VERSION 5.4 ;
NAMESCASESENSITIVE ON ;
BUSBITCHARS "[]" ;
DIVIDERCHAR "/" ;
UNITS
  DATABASE MICRONS 2000 ;
END UNITS
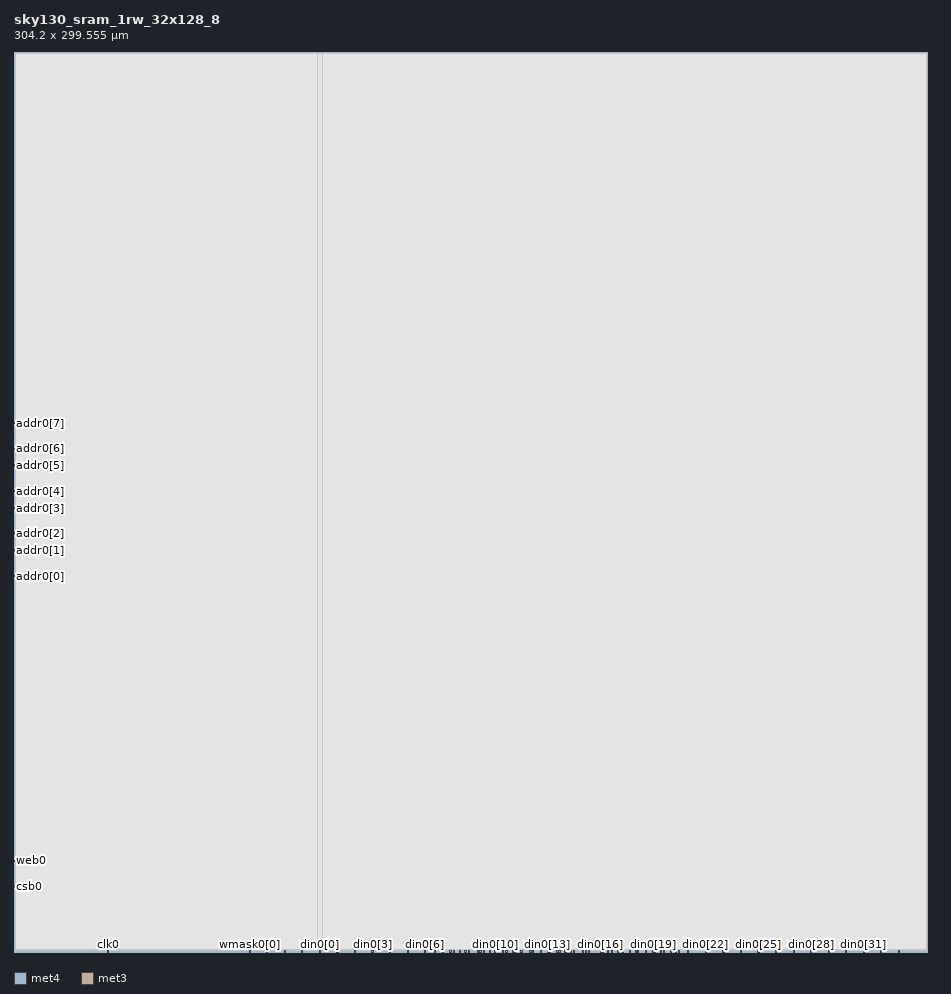
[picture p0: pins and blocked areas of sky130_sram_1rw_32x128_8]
MACRO sky130_sram_1rw_32x128_8
   CLASS BLOCK ;
   SIZE 304.2 BY 299.555 ;
   SYMMETRY X Y R90 ;
   PIN din0[0]
      DIRECTION INPUT ;
      PORT
         LAYER met4 ;
         RECT  101.62 0.0 102.0 0.38 ;
      END
   END din0[0]
   PIN din0[1]
      DIRECTION INPUT ;
      PORT
         LAYER met4 ;
         RECT  107.46 0.0 107.84 0.38 ;
      END
   END din0[1]
   PIN din0[2]
      DIRECTION INPUT ;
      PORT
         LAYER met4 ;
         RECT  113.3 0.0 113.68 0.38 ;
      END
   END din0[2]
   PIN din0[3]
      DIRECTION INPUT ;
      PORT
         LAYER met4 ;
         RECT  119.14 0.0 119.52 0.38 ;
      END
   END din0[3]
   PIN din0[4]
      DIRECTION INPUT ;
      PORT
         LAYER met4 ;
         RECT  124.98 0.0 125.36 0.38 ;
      END
   END din0[4]
   PIN din0[5]
      DIRECTION INPUT ;
      PORT
         LAYER met4 ;
         RECT  130.82 0.0 131.2 0.38 ;
      END
   END din0[5]
   PIN din0[6]
      DIRECTION INPUT ;
      PORT
         LAYER met4 ;
         RECT  136.66 0.0 137.04 0.38 ;
      END
   END din0[6]
   PIN din0[7]
      DIRECTION INPUT ;
      PORT
         LAYER met4 ;
         RECT  142.5 0.0 142.88 0.38 ;
      END
   END din0[7]
   PIN din0[8]
      DIRECTION INPUT ;
      PORT
         LAYER met4 ;
         RECT  148.34 0.0 148.72 0.38 ;
      END
   END din0[8]
   PIN din0[9]
      DIRECTION INPUT ;
      PORT
         LAYER met4 ;
         RECT  154.18 0.0 154.56 0.38 ;
      END
   END din0[9]
   PIN din0[10]
      DIRECTION INPUT ;
      PORT
         LAYER met4 ;
         RECT  160.02 0.0 160.4 0.38 ;
      END
   END din0[10]
   PIN din0[11]
      DIRECTION INPUT ;
      PORT
         LAYER met4 ;
         RECT  165.86 0.0 166.24 0.38 ;
      END
   END din0[11]
   PIN din0[12]
      DIRECTION INPUT ;
      PORT
         LAYER met4 ;
         RECT  171.7 0.0 172.08 0.38 ;
      END
   END din0[12]
   PIN din0[13]
      DIRECTION INPUT ;
      PORT
         LAYER met4 ;
         RECT  177.54 0.0 177.92 0.38 ;
      END
   END din0[13]
   PIN din0[14]
      DIRECTION INPUT ;
      PORT
         LAYER met4 ;
         RECT  183.38 0.0 183.76 0.38 ;
      END
   END din0[14]
   PIN din0[15]
      DIRECTION INPUT ;
      PORT
         LAYER met4 ;
         RECT  189.22 0.0 189.6 0.38 ;
      END
   END din0[15]
   PIN din0[16]
      DIRECTION INPUT ;
      PORT
         LAYER met4 ;
         RECT  195.06 0.0 195.44 0.38 ;
      END
   END din0[16]
   PIN din0[17]
      DIRECTION INPUT ;
      PORT
         LAYER met4 ;
         RECT  200.9 0.0 201.28 0.38 ;
      END
   END din0[17]
   PIN din0[18]
      DIRECTION INPUT ;
      PORT
         LAYER met4 ;
         RECT  206.74 0.0 207.12 0.38 ;
      END
   END din0[18]
   PIN din0[19]
      DIRECTION INPUT ;
      PORT
         LAYER met4 ;
         RECT  212.58 0.0 212.96 0.38 ;
      END
   END din0[19]
   PIN din0[20]
      DIRECTION INPUT ;
      PORT
         LAYER met4 ;
         RECT  218.42 0.0 218.8 0.38 ;
      END
   END din0[20]
   PIN din0[21]
      DIRECTION INPUT ;
      PORT
         LAYER met4 ;
         RECT  224.26 0.0 224.64 0.38 ;
      END
   END din0[21]
   PIN din0[22]
      DIRECTION INPUT ;
      PORT
         LAYER met4 ;
         RECT  230.1 0.0 230.48 0.38 ;
      END
   END din0[22]
   PIN din0[23]
      DIRECTION INPUT ;
      PORT
         LAYER met4 ;
         RECT  235.94 0.0 236.32 0.38 ;
      END
   END din0[23]
   PIN din0[24]
      DIRECTION INPUT ;
      PORT
         LAYER met4 ;
         RECT  241.78 0.0 242.16 0.38 ;
      END
   END din0[24]
   PIN din0[25]
      DIRECTION INPUT ;
      PORT
         LAYER met4 ;
         RECT  247.62 0.0 248.0 0.38 ;
      END
   END din0[25]
   PIN din0[26]
      DIRECTION INPUT ;
      PORT
         LAYER met4 ;
         RECT  253.46 0.0 253.84 0.38 ;
      END
   END din0[26]
   PIN din0[27]
      DIRECTION INPUT ;
      PORT
         LAYER met4 ;
         RECT  259.3 0.0 259.68 0.38 ;
      END
   END din0[27]
   PIN din0[28]
      DIRECTION INPUT ;
      PORT
         LAYER met4 ;
         RECT  265.14 0.0 265.52 0.38 ;
      END
   END din0[28]
   PIN din0[29]
      DIRECTION INPUT ;
      PORT
         LAYER met4 ;
         RECT  270.98 0.0 271.36 0.38 ;
      END
   END din0[29]
   PIN din0[30]
      DIRECTION INPUT ;
      PORT
         LAYER met4 ;
         RECT  276.82 0.0 277.2 0.38 ;
      END
   END din0[30]
   PIN din0[31]
      DIRECTION INPUT ;
      PORT
         LAYER met4 ;
         RECT  282.66 0.0 283.04 0.38 ;
      END
   END din0[31]
   PIN din0[32]
      DIRECTION INPUT ;
      PORT
         LAYER met4 ;
         RECT  288.5 0.0 288.88 0.38 ;
      END
   END din0[32]
   PIN addr0[0]
      DIRECTION INPUT ;
      PORT
         LAYER met3 ;
         RECT  0.0 124.95 0.38 125.33 ;
      END
   END addr0[0]
   PIN addr0[1]
      DIRECTION INPUT ;
      PORT
         LAYER met3 ;
         RECT  0.0 133.45 0.38 133.83 ;
      END
   END addr0[1]
   PIN addr0[2]
      DIRECTION INPUT ;
      PORT
         LAYER met3 ;
         RECT  0.0 139.09 0.38 139.47 ;
      END
   END addr0[2]
   PIN addr0[3]
      DIRECTION INPUT ;
      PORT
         LAYER met3 ;
         RECT  0.0 147.59 0.38 147.97 ;
      END
   END addr0[3]
   PIN addr0[4]
      DIRECTION INPUT ;
      PORT
         LAYER met3 ;
         RECT  0.0 153.23 0.38 153.61 ;
      END
   END addr0[4]
   PIN addr0[5]
      DIRECTION INPUT ;
      PORT
         LAYER met3 ;
         RECT  0.0 161.73 0.38 162.11 ;
      END
   END addr0[5]
   PIN addr0[6]
      DIRECTION INPUT ;
      PORT
         LAYER met3 ;
         RECT  0.0 167.37 0.38 167.75 ;
      END
   END addr0[6]
   PIN addr0[7]
      DIRECTION INPUT ;
      PORT
         LAYER met3 ;
         RECT  0.0 175.87 0.38 176.25 ;
      END
   END addr0[7]
   PIN csb0
      DIRECTION INPUT ;
      PORT
         LAYER met3 ;
         RECT  0.0 21.61 0.38 21.99 ;
      END
   END csb0
   PIN web0
      DIRECTION INPUT ;
      PORT
         LAYER met3 ;
         RECT  0.0 30.11 0.38 30.49 ;
      END
   END web0
   PIN clk0
      DIRECTION INPUT ;
      PORT
         LAYER met4 ;
         RECT  31.1 0.0 31.48 0.38 ;
      END
   END clk0
   PIN wmask0[0]
      DIRECTION INPUT ;
      PORT
         LAYER met4 ;
         RECT  78.26 0.0 78.64 0.38 ;
      END
   END wmask0[0]
   PIN wmask0[1]
      DIRECTION INPUT ;
      PORT
         LAYER met4 ;
         RECT  84.1 0.0 84.48 0.38 ;
      END
   END wmask0[1]
   PIN wmask0[2]
      DIRECTION INPUT ;
      PORT
         LAYER met4 ;
         RECT  89.94 0.0 90.32 0.38 ;
      END
   END wmask0[2]
   PIN wmask0[3]
      DIRECTION INPUT ;
      PORT
         LAYER met4 ;
         RECT  95.78 0.0 96.16 0.38 ;
      END
   END wmask0[3]
   PIN spare_wen0
      DIRECTION INPUT ;
      PORT
         LAYER met4 ;
         RECT  294.34 0.0 294.72 0.38 ;
      END
   END spare_wen0
   PIN dout0[0]
      DIRECTION OUTPUT ;
      PORT
         LAYER met4 ;
         RECT  139.985 0.0 140.365 0.38 ;
      END
   END dout0[0]
   PIN dout0[1]
      DIRECTION OUTPUT ;
      PORT
         LAYER met4 ;
         RECT  145.1 0.0 145.48 0.38 ;
      END
   END dout0[1]
   PIN dout0[2]
      DIRECTION OUTPUT ;
      PORT
         LAYER met4 ;
         RECT  146.25 0.0 146.63 0.38 ;
      END
   END dout0[2]
   PIN dout0[3]
      DIRECTION OUTPUT ;
      PORT
         LAYER met4 ;
         RECT  150.1 0.0 150.48 0.38 ;
      END
   END dout0[3]
   PIN dout0[4]
      DIRECTION OUTPUT ;
      PORT
         LAYER met4 ;
         RECT  151.25 0.0 151.63 0.38 ;
      END
   END dout0[4]
   PIN dout0[5]
      DIRECTION OUTPUT ;
      PORT
         LAYER met4 ;
         RECT  155.1 0.0 155.48 0.38 ;
      END
   END dout0[5]
   PIN dout0[6]
      DIRECTION OUTPUT ;
      PORT
         LAYER met4 ;
         RECT  156.25 0.0 156.63 0.38 ;
      END
   END dout0[6]
   PIN dout0[7]
      DIRECTION OUTPUT ;
      PORT
         LAYER met4 ;
         RECT  158.215 0.0 158.595 0.38 ;
      END
   END dout0[7]
   PIN dout0[8]
      DIRECTION OUTPUT ;
      PORT
         LAYER met4 ;
         RECT  162.63 0.0 163.01 0.38 ;
      END
   END dout0[8]
   PIN dout0[9]
      DIRECTION OUTPUT ;
      PORT
         LAYER met4 ;
         RECT  163.72 0.0 164.1 0.38 ;
      END
   END dout0[9]
   PIN dout0[10]
      DIRECTION OUTPUT ;
      PORT
         LAYER met4 ;
         RECT  166.55 0.0 166.93 0.38 ;
      END
   END dout0[10]
   PIN dout0[11]
      DIRECTION OUTPUT ;
      PORT
         LAYER met4 ;
         RECT  168.72 0.0 169.1 0.38 ;
      END
   END dout0[11]
   PIN dout0[12]
      DIRECTION OUTPUT ;
      PORT
         LAYER met4 ;
         RECT  172.63 0.0 173.01 0.38 ;
      END
   END dout0[12]
   PIN dout0[13]
      DIRECTION OUTPUT ;
      PORT
         LAYER met4 ;
         RECT  175.1 0.0 175.48 0.38 ;
      END
   END dout0[13]
   PIN dout0[14]
      DIRECTION OUTPUT ;
      PORT
         LAYER met4 ;
         RECT  178.23 0.0 178.61 0.38 ;
      END
   END dout0[14]
   PIN dout0[15]
      DIRECTION OUTPUT ;
      PORT
         LAYER met4 ;
         RECT  181.395 0.0 181.775 0.38 ;
      END
   END dout0[15]
   PIN dout0[16]
      DIRECTION OUTPUT ;
      PORT
         LAYER met4 ;
         RECT  180.705 0.0 181.085 0.38 ;
      END
   END dout0[16]
   PIN dout0[17]
      DIRECTION OUTPUT ;
      PORT
         LAYER met4 ;
         RECT  185.1 0.0 185.48 0.38 ;
      END
   END dout0[17]
   PIN dout0[18]
      DIRECTION OUTPUT ;
      PORT
         LAYER met4 ;
         RECT  186.25 0.0 186.63 0.38 ;
      END
   END dout0[18]
   PIN dout0[19]
      DIRECTION OUTPUT ;
      PORT
         LAYER met4 ;
         RECT  190.1 0.0 190.48 0.38 ;
      END
   END dout0[19]
   PIN dout0[20]
      DIRECTION OUTPUT ;
      PORT
         LAYER met4 ;
         RECT  191.25 0.0 191.63 0.38 ;
      END
   END dout0[20]
   PIN dout0[21]
      DIRECTION OUTPUT ;
      PORT
         LAYER met4 ;
         RECT  195.75 0.0 196.13 0.38 ;
      END
   END dout0[21]
   PIN dout0[22]
      DIRECTION OUTPUT ;
      PORT
         LAYER met4 ;
         RECT  197.63 0.0 198.01 0.38 ;
      END
   END dout0[22]
   PIN dout0[23]
      DIRECTION OUTPUT ;
      PORT
         LAYER met4 ;
         RECT  198.72 0.0 199.1 0.38 ;
      END
   END dout0[23]
   PIN dout0[24]
      DIRECTION OUTPUT ;
      PORT
         LAYER met4 ;
         RECT  202.63 0.0 203.01 0.38 ;
      END
   END dout0[24]
   PIN dout0[25]
      DIRECTION OUTPUT ;
      PORT
         LAYER met4 ;
         RECT  204.935 0.0 205.315 0.38 ;
      END
   END dout0[25]
   PIN dout0[26]
      DIRECTION OUTPUT ;
      PORT
         LAYER met4 ;
         RECT  207.63 0.0 208.01 0.38 ;
      END
   END dout0[26]
   PIN dout0[27]
      DIRECTION OUTPUT ;
      PORT
         LAYER met4 ;
         RECT  210.1 0.0 210.48 0.38 ;
      END
   END dout0[27]
   PIN dout0[28]
      DIRECTION OUTPUT ;
      PORT
         LAYER met4 ;
         RECT  213.27 0.0 213.65 0.38 ;
      END
   END dout0[28]
   PIN dout0[29]
      DIRECTION OUTPUT ;
      PORT
         LAYER met4 ;
         RECT  215.1 0.0 215.48 0.38 ;
      END
   END dout0[29]
   PIN dout0[30]
      DIRECTION OUTPUT ;
      PORT
         LAYER met4 ;
         RECT  216.25 0.0 216.63 0.38 ;
      END
   END dout0[30]
   PIN dout0[31]
      DIRECTION OUTPUT ;
      PORT
         LAYER met4 ;
         RECT  220.1 0.0 220.48 0.38 ;
      END
   END dout0[31]
   PIN dout0[32]
      DIRECTION OUTPUT ;
      PORT
         LAYER met4 ;
         RECT  221.25 0.0 221.63 0.38 ;
      END
   END dout0[32]
   PIN vccd1
      DIRECTION INOUT ;
      USE POWER ; 
      SHAPE ABUTMENT ; 
      PORT
      END
   END vccd1
   PIN vssd1
      DIRECTION INOUT ;
      USE GROUND ; 
      SHAPE ABUTMENT ; 
      PORT
      END
   END vssd1
   OBS
   LAYER  met1 ;
      RECT  0.62 0.62 303.58 298.935 ;
   LAYER  met2 ;
      RECT  0.62 0.62 303.58 298.935 ;
   LAYER  met3 ;
      RECT  0.98 0.62 303.58 124.35 ;
      RECT  0.98 124.35 303.58 125.93 ;
      RECT  0.98 125.93 303.58 298.935 ;
      RECT  0.62 125.93 0.98 132.85 ;
      RECT  0.62 134.43 0.98 138.49 ;
      RECT  0.62 140.07 0.98 146.99 ;
      RECT  0.62 148.57 0.98 152.63 ;
      RECT  0.62 154.21 0.98 161.13 ;
      RECT  0.62 162.71 0.98 166.77 ;
      RECT  0.62 168.35 0.98 175.27 ;
      RECT  0.62 176.85 0.98 298.935 ;
      RECT  0.62 0.62 0.98 21.01 ;
      RECT  0.62 22.59 0.98 29.51 ;
      RECT  0.62 31.09 0.98 124.35 ;
   LAYER  met4 ;
      RECT  0.62 0.98 101.02 298.935 ;
      RECT  101.02 0.98 102.6 298.935 ;
      RECT  102.6 0.98 303.58 298.935 ;
      RECT  102.6 0.62 106.86 0.98 ;
      RECT  108.44 0.62 112.7 0.98 ;
      RECT  114.28 0.62 118.54 0.98 ;
      RECT  120.12 0.62 124.38 0.98 ;
      RECT  125.96 0.62 130.22 0.98 ;
      RECT  131.8 0.62 136.06 0.98 ;
      RECT  225.24 0.62 229.5 0.98 ;
      RECT  231.08 0.62 235.34 0.98 ;
      RECT  236.92 0.62 241.18 0.98 ;
      RECT  242.76 0.62 247.02 0.98 ;
      RECT  248.6 0.62 252.86 0.98 ;
      RECT  254.44 0.62 258.7 0.98 ;
      RECT  260.28 0.62 264.54 0.98 ;
      RECT  266.12 0.62 270.38 0.98 ;
      RECT  271.96 0.62 276.22 0.98 ;
      RECT  277.8 0.62 282.06 0.98 ;
      RECT  283.64 0.62 287.9 0.98 ;
      RECT  0.62 0.62 30.5 0.98 ;
      RECT  32.08 0.62 77.66 0.98 ;
      RECT  79.24 0.62 83.5 0.98 ;
      RECT  85.08 0.62 89.34 0.98 ;
      RECT  90.92 0.62 95.18 0.98 ;
      RECT  96.76 0.62 101.02 0.98 ;
      RECT  289.48 0.62 293.74 0.98 ;
      RECT  295.32 0.62 303.58 0.98 ;
      RECT  137.64 0.62 139.385 0.98 ;
      RECT  140.965 0.62 141.9 0.98 ;
      RECT  143.48 0.62 144.5 0.98 ;
      RECT  147.23 0.62 147.74 0.98 ;
      RECT  149.32 0.62 149.5 0.98 ;
      RECT  152.23 0.62 153.58 0.98 ;
      RECT  157.23 0.62 157.615 0.98 ;
      RECT  159.195 0.62 159.42 0.98 ;
      RECT  161.0 0.62 162.03 0.98 ;
      RECT  164.7 0.62 165.26 0.98 ;
      RECT  167.53 0.62 168.12 0.98 ;
      RECT  169.7 0.62 171.1 0.98 ;
      RECT  173.61 0.62 174.5 0.98 ;
      RECT  176.08 0.62 176.94 0.98 ;
      RECT  182.375 0.62 182.78 0.98 ;
      RECT  179.21 0.62 180.105 0.98 ;
      RECT  184.36 0.62 184.5 0.98 ;
      RECT  187.23 0.62 188.62 0.98 ;
      RECT  192.23 0.62 194.46 0.98 ;
      RECT  196.73 0.62 197.03 0.98 ;
      RECT  199.7 0.62 200.3 0.98 ;
      RECT  201.88 0.62 202.03 0.98 ;
      RECT  203.61 0.62 204.335 0.98 ;
      RECT  205.915 0.62 206.14 0.98 ;
      RECT  208.61 0.62 209.5 0.98 ;
      RECT  211.08 0.62 211.98 0.98 ;
      RECT  214.25 0.62 214.5 0.98 ;
      RECT  217.23 0.62 217.82 0.98 ;
      RECT  219.4 0.62 219.5 0.98 ;
      RECT  222.23 0.62 223.66 0.98 ;
   END
END    sky130_sram_1rw_32x128_8
END    LIBRARY
